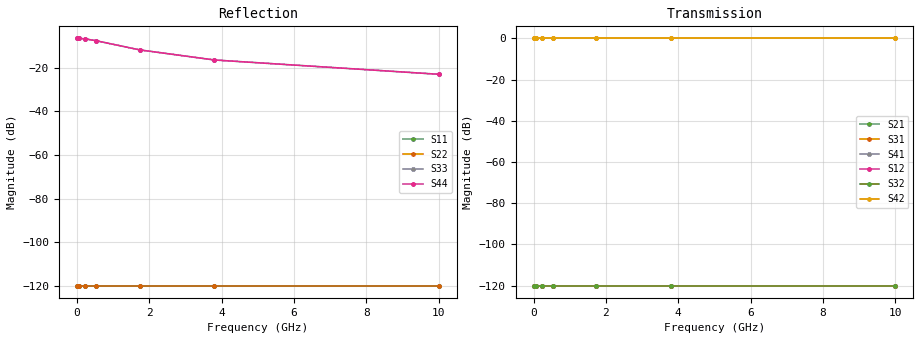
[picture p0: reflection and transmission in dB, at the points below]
! Copyright 2015, Texas Instruments Incorporated. All rights reserved.
! Generated by program util_convert_s2p_term_to_s4p on 05-08-2017 16:49:25
!  1 ----xxxxxxxxxxxxxxxxxx---- 3
!  xxxxxxxxxxxxxxxxxx
!  (Input) xxxxxxxxxxxxxxxxxx  (Output) <--- Termination looking in to TX
!  xxxxxxxxxxxxxxxxxx
!  2 ----xxxxxxxxxxxxxxxxxx---- 4
! FREQ  S11  S12  S13  S14
!  S21  S22  S23  S24
!  S31  S32  S33  S34
!  S41  S42  S43  S44
!  DB  ANG  DB  ANG  DB  ANG  DB  ANG
# HZ S DB R 50.00
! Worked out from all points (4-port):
!   401 points, 1 MHz to 10 GHz, reference 50 ohm
!   strongest paths, dB at 1 MHz, 10 MHz, 100 MHz, 1 GHz, 10 GHz:
!     S42: 0.0, 0.0, 0.0, 0.0, 0.0
!     S31: 0.0, 0.0, 0.0, 0.0, 0.0
!     S43: -5.6, -5.6, -5.5, -2.4, -0.2
!     S41: -120.0, -120.0, -120.0, -120.0, -120.0
!     S32: -120.0, -120.0, -120.0, -120.0, -120.0
!     S21: -120.0, -120.0, -120.0, -120.0, -120.0
!   lowest |S11| = -120.0 dB at 1 MHz (marker M1), VSWR 1.00, Z = 50 + j0 ohm
!   |S11| at or under -10 dB: start of sweep to end of sweep
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1000000  -120.00 0.0  -120.00 0.0  -120.00 0.0  -120.00 0.0
         -120.00 0.0  -120.00 0.0  -120.00 0.0  -120.00 0.0
         0.00 0.0  -120.00 0.0  -6.42 -0.1  -5.64 0.0
         -120.00 0.0  0.00 0.0  -5.64 0.0  -6.42 -0.1
6.45654e7  -120.00 0.0  -120.00 0.0  -120.00 0.0  -120.00 0.0
           -120.00 0.0  -120.00 0.0  -120.00 0.0  -120.00 0.0
           0.00 0.0  -120.00 0.0  -6.44 -3.3  -5.59 3.0
           -120.00 0.0  0.00 0.0  -5.59 3.0  -6.44 -3.3
2.34423e8  -120.00 0.0  -120.00 0.0  -120.00 0.0  -120.00 0.0
           -120.00 0.0  -120.00 0.0  -120.00 0.0  -120.00 0.0
           0.00 0.0  -120.00 0.0  -6.67 -11.7  -5.13 9.8
           -120.00 0.0  0.00 0.0  -5.13 9.8  -6.67 -11.7
5.24807e8  -120.00 0.0  -120.00 0.0  -120.00 0.0  -120.00 0.0
           -120.00 0.0  -120.00 0.0  -120.00 0.0  -120.00 0.0
           0.00 0.0  -120.00 0.0  -7.49 -24.0  -3.91 15.6
           -120.00 0.0  0.00 0.0  -3.91 15.6  -7.49 -24.0
1.7378e9  -120.00 0.0  -120.00 0.0  -120.00 0.0  -120.00 0.0
          -120.00 0.0  -120.00 0.0  -120.00 0.0  -120.00 0.0
          0.00 0.0  -120.00 0.0  -11.72 -49.1  -1.38 13.3
          -120.00 0.0  0.00 0.0  -1.38 13.3  -11.72 -49.1
3.80189e9  -120.00 0.0  -120.00 0.0  -120.00 0.0  -120.00 0.0
           -120.00 0.0  -120.00 0.0  -120.00 0.0  -120.00 0.0
           0.00 0.0  -120.00 0.0  -16.35 -61.3  -0.57 8.2
           -120.00 0.0  0.00 0.0  -0.57 8.2  -16.35 -61.3
1e10  -120.00 0.0  -120.00 0.0  -120.00 0.0  -120.00 0.0
      -120.00 0.0  -120.00 0.0  -120.00 0.0  -120.00 0.0
      0.00 0.0  -120.00 0.0  -22.91 -71.2  -0.18 4.0
      -120.00 0.0  0.00 0.0  -0.18 4.0  -22.91 -71.2
